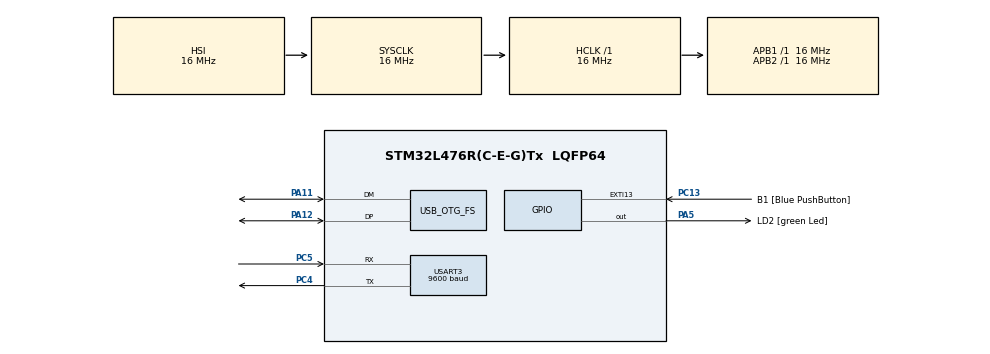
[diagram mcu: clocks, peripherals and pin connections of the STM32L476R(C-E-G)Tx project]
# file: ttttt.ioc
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Mcu.Family=STM32L4
Mcu.Name=STM32L476R(C-E-G)Tx
Mcu.Package=LQFP64
NVIC.OTG_FS_IRQn=true\:0\:0\:false\:false\:true
NVIC.PriorityGroup=NVIC_PRIORITYGROUP_4
PA11.Mode=Host_Only
PA11.Signal=USB_OTG_FS_DM
PA12.Mode=Host_Only
PA12.Signal=USB_OTG_FS_DP
PA13.GPIO_Label=TMS
PA13.Signal=SYS_JTMS-SWDIO
PA14.GPIO_Label=TCK
PA14.Signal=SYS_JTCK-SWCLK
PA2.GPIO_Label=USART_TX
PA2.GPIO_Mode=GPIO_MODE_AF_PP
PA2.GPIO_PuPd=GPIO_NOPULL
PA2.GPIO_Speed=GPIO_SPEED_FREQ_VERY_HIGH
PA2.Signal=USART2_TX
PA3.GPIO_Label=USART_RX
PA3.GPIO_Mode=GPIO_MODE_AF_PP
PA3.GPIO_PuPd=GPIO_NOPULL
PA3.GPIO_Speed=GPIO_SPEED_FREQ_VERY_HIGH
PA3.Signal=USART2_RX
PA5.GPIO_Label=LD2 [green Led]
PA5.GPIO_ModeDefaultOutputPP=GPIO_MODE_OUTPUT_PP
PA5.GPIO_PuPd=GPIO_NOPULL
PA5.GPIO_Speed=GPIO_SPEED_FREQ_LOW
PA5.Signal=GPIO_Output
PB3.GPIO_Label=SWO
PB3.Signal=SYS_JTDO-SWO
PC13.GPIO_Label=B1 [Blue PushButton]
PC13.GPIO_ModeDefaultEXTI=GPIO_MODE_EVT_RISING
PC13.GPIO_PuPd=GPIO_NOPULL
PC13.Signal=GPXTI13
PC14/OSC32_IN.Signal=RCC_OSC32_IN
PC15/OSC32_OUT.Signal=RCC_OSC32_OUT
PC4.Mode=Asynchronous
PC4.Signal=USART3_TX
PC5.Mode=Asynchronous
PC5.Signal=USART3_RX
PH0/OSC_IN.Signal=RCC_OSC_IN
PH1/OSC_OUT.Signal=RCC_OSC_OUT
ProjectManager.HeapSize=0x200
ProjectManager.StackSize=0x400
ProjectManager.TargetToolchain=SW4STM32
RCC.ADCFreq_Value=48000000
RCC.AHBFreq_Value=16000000
RCC.APB1Freq_Value=16000000
RCC.APB1TimFreq_Value=16000000
RCC.APB2Freq_Value=16000000
RCC.APB2TimFreq_Value=16000000
RCC.CK48CLockSelection=RCC_USBCLKSOURCE_PLL
RCC.CortexFreq_Value=16000000
RCC.HCLKFreq_Value=16000000
RCC.HSE_VALUE=8000000
RCC.HSI_VALUE=16000000
RCC.LSE_VALUE=32768
RCC.MSI_VALUE=4000000
RCC.PLLN=24
RCC.PLLSAI1N=24
RCC.PREFETCH_ENABLE=1
RCC.SYSCLKFreq_VALUE=16000000
RCC.SYSCLKSource=RCC_SYSCLKSOURCE_HSI
RCC.USBFreq_Value=48000000
RCC.VCOOutputFreq_Value=96000000
USART3.BaudRate=9600
USART3.WordLength=UART_WORDLENGTH_8B
USB_HOST.USBH_HandleTypeDef=hUsbHostFS
USB_HOST.VirtualModeFS=Hid
USB_OTG_FS.phy_itface=HCD_PHY_EMBEDDED
VP_USB_HOST_VS_USB_HOST_HID_FS.Mode=HID_FS
board=NUCLEO-L476RG

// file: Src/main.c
/**
  ******************************************************************************
  * File Name          : main.c
  * Description        : Main program body
  ******************************************************************************
  *
  * Copyright (c) 2017 STMicroelectronics International N.V.
  * All rights reserved.
  *
  * Redistribution and use in source and binary forms, with or without
  * modification, are permitted, provided that the following conditions are met:
  *
  * 1. Redistribution of source code must retain the above copyright notice,
  *    this list of conditions and the following disclaimer.
  * 2. Redistributions in binary form must reproduce the above copyright notice,
  *    this list of conditions and the following disclaimer in the documentation
  *    and/or other materials provided with the distribution.
  * 3. Neither the name of STMicroelectronics nor the names of other
  *    contributors to this software may be used to endorse or promote products
  *    derived from this software without specific written permission.
  * 4. This software, including modifications and/or derivative works of this
  *    software, must execute solely and exclusively on microcontroller or
  *    microprocessor devices manufactured by or for STMicroelectronics.
  * 5. Redistribution and use of this software other than as permitted under
  *    this license is void and will automatically terminate your rights under
  *    this license.
  *
  * THIS SOFTWARE IS PROVIDED BY STMICROELECTRONICS AND CONTRIBUTORS "AS IS"
  * AND ANY EXPRESS, IMPLIED OR STATUTORY WARRANTIES, INCLUDING, BUT NOT
  * LIMITED TO, THE IMPLIED WARRANTIES OF MERCHANTABILITY, FITNESS FOR A
  * PARTICULAR PURPOSE AND NON-INFRINGEMENT OF THIRD PARTY INTELLECTUAL PROPERTY
  * RIGHTS ARE DISCLAIMED TO THE FULLEST EXTENT PERMITTED BY LAW. IN NO EVENT
  * SHALL STMICROELECTRONICS OR CONTRIBUTORS BE LIABLE FOR ANY DIRECT, INDIRECT,
  * INCIDENTAL, SPECIAL, EXEMPLARY, OR CONSEQUENTIAL DAMAGES (INCLUDING, BUT NOT
  * LIMITED TO, PROCUREMENT OF SUBSTITUTE GOODS OR SERVICES; LOSS OF USE, DATA,
  * OR PROFITS; OR BUSINESS INTERRUPTION) HOWEVER CAUSED AND ON ANY THEORY OF
  * LIABILITY, WHETHER IN CONTRACT, STRICT LIABILITY, OR TORT (INCLUDING
  * NEGLIGENCE OR OTHERWISE) ARISING IN ANY WAY OUT OF THE USE OF THIS SOFTWARE,
  * EVEN IF ADVISED OF THE POSSIBILITY OF SUCH DAMAGE.
  *
  ******************************************************************************
  */
#include "main.h"
#include "stm32l4xx_hal.h"
#include "usb_host.h"
#include "global_var.h"
#include <stdio.h>
#include <stdlib.h>

/* USER CODE BEGIN PV */
/* Private variables ---------------------------------------------------------*/
status = 0;
/* USER CODE END PV */

void SystemClock_Config(void);
void Error_Handler(void);
static void MX_GPIO_Init(void);
static void MX_USART3_UART_Init(void);
void MX_USB_HOST_Process(void);

/* USER CODE BEGIN PFP */
/* Private function prototypes -----------------------------------------------*/

/* USER CODE END PFP */

int main(void)
{

  /* MCU Configuration----------------------------------------------------------*/

  /* Reset of all peripherals, Initializes the Flash interface and the Systick. */
  HAL_Init();

  /* Configure the system clock */
  SystemClock_Config();

  /* Initialize all configured peripherals */
  MX_GPIO_Init();
  MX_USART3_UART_Init();
  MX_USB_HOST_Init();

  /* USER CODE BEGIN 2 */
  Timer_Init();
  PWM_Init();
  /* USER CODE END 2 */

  /* Infinite loop */
  while (1)
  {
    MX_USB_HOST_Process();
  }

}

/** System Clock Configuration
*/
void SystemClock_Config(void)
{

  RCC_OscInitTypeDef RCC_OscInitStruct;
  RCC_ClkInitTypeDef RCC_ClkInitStruct;
  RCC_PeriphCLKInitTypeDef PeriphClkInit;

    /**Initializes the CPU, AHB and APB busses clocks
    */
  RCC_OscInitStruct.OscillatorType = RCC_OSCILLATORTYPE_HSI|RCC_OSCILLATORTYPE_MSI;
  RCC_OscInitStruct.HSIState = RCC_HSI_ON;
  RCC_OscInitStruct.HSICalibrationValue = 16;
  RCC_OscInitStruct.MSIState = RCC_MSI_ON;
  RCC_OscInitStruct.MSICalibrationValue = 0;
  RCC_OscInitStruct.MSIClockRange = RCC_MSIRANGE_6;
  RCC_OscInitStruct.PLL.PLLState = RCC_PLL_ON;
  RCC_OscInitStruct.PLL.PLLSource = RCC_PLLSOURCE_MSI;
  RCC_OscInitStruct.PLL.PLLM = 1;
  RCC_OscInitStruct.PLL.PLLN = 24;
  RCC_OscInitStruct.PLL.PLLP = RCC_PLLP_DIV7;
  RCC_OscInitStruct.PLL.PLLQ = RCC_PLLQ_DIV2;
  RCC_OscInitStruct.PLL.PLLR = RCC_PLLR_DIV2;
  if (HAL_RCC_OscConfig(&RCC_OscInitStruct) != HAL_OK)
  {
    Error_Handler();
  }

    /**Initializes the CPU, AHB and APB busses clocks
    */
  RCC_ClkInitStruct.ClockType = RCC_CLOCKTYPE_HCLK|RCC_CLOCKTYPE_SYSCLK
                              |RCC_CLOCKTYPE_PCLK1|RCC_CLOCKTYPE_PCLK2;
  RCC_ClkInitStruct.SYSCLKSource = RCC_SYSCLKSOURCE_HSI;
  RCC_ClkInitStruct.AHBCLKDivider = RCC_SYSCLK_DIV1;
  RCC_ClkInitStruct.APB1CLKDivider = RCC_HCLK_DIV1;
  RCC_ClkInitStruct.APB2CLKDivider = RCC_HCLK_DIV1;

  if (HAL_RCC_ClockConfig(&RCC_ClkInitStruct, FLASH_LATENCY_0) != HAL_OK)
  {
    Error_Handler();
  }

  PeriphClkInit.PeriphClockSelection = RCC_PERIPHCLK_USART3|RCC_PERIPHCLK_USB;
  PeriphClkInit.Usart3ClockSelection = RCC_USART3CLKSOURCE_PCLK1;
  PeriphClkInit.UsbClockSelection = RCC_USBCLKSOURCE_PLL;
  if (HAL_RCCEx_PeriphCLKConfig(&PeriphClkInit) != HAL_OK)
  {
    Error_Handler();
  }

    /**Configure the main internal regulator output voltage
    */
  if (HAL_PWREx_ControlVoltageScaling(PWR_REGULATOR_VOLTAGE_SCALE1) != HAL_OK)
  {
    Error_Handler();
  }

    /**Configure the Systick interrupt time
    */
  HAL_SYSTICK_Config(HAL_RCC_GetHCLKFreq()/1000);

    /**Configure the Systick
    */
  HAL_SYSTICK_CLKSourceConfig(SYSTICK_CLKSOURCE_HCLK);

    /**Enable MSI Auto calibration
    */
  HAL_RCCEx_EnableMSIPLLMode();

  /* SysTick_IRQn interrupt configuration */
  HAL_NVIC_SetPriority(SysTick_IRQn, 0, 0);
}

/* USART3 init function */
static void MX_USART3_UART_Init(void)
{

  huart3.Instance = USART3;
  huart3.Init.BaudRate = 9600;
  huart3.Init.WordLength = UART_WORDLENGTH_8B;
  huart3.Init.StopBits = UART_STOPBITS_1;
  huart3.Init.Parity = UART_PARITY_NONE;
  huart3.Init.Mode = UART_MODE_TX_RX;
  huart3.Init.HwFlowCtl = UART_HWCONTROL_NONE;
  huart3.Init.OverSampling = UART_OVERSAMPLING_16;
  huart3.Init.OneBitSampling = UART_ONE_BIT_SAMPLE_DISABLE;
  huart3.AdvancedInit.AdvFeatureInit = UART_ADVFEATURE_NO_INIT;
  if (HAL_UART_Init(&huart3) != HAL_OK)
  {
    Error_Handler();
  }

}

/** Configure pins as
        * Analog
        * Input
        * Output
        * EVENT_OUT
        * EXTI
     PA2   ------> USART2_TX
     PA3   ------> USART2_RX
*/
static void MX_GPIO_Init(void)
{

  GPIO_InitTypeDef GPIO_InitStruct;

  /* GPIO Ports Clock Enable */
  __HAL_RCC_GPIOC_CLK_ENABLE();
  __HAL_RCC_GPIOH_CLK_ENABLE();
  __HAL_RCC_GPIOA_CLK_ENABLE();
  __HAL_RCC_GPIOB_CLK_ENABLE();

  /*Configure GPIO pin : B1_Pin */
  GPIO_InitStruct.Pin = B1_Pin;
  GPIO_InitStruct.Mode = GPIO_MODE_EVT_RISING;
  GPIO_InitStruct.Pull = GPIO_NOPULL;
  HAL_GPIO_Init(B1_GPIO_Port, &GPIO_InitStruct);

  /*Configure GPIO pins : USART_TX_Pin USART_RX_Pin */
  GPIO_InitStruct.Pin = USART_TX_Pin|USART_RX_Pin;
  GPIO_InitStruct.Mode = GPIO_MODE_AF_PP;
  GPIO_InitStruct.Pull = GPIO_NOPULL;
  GPIO_InitStruct.Speed = GPIO_SPEED_FREQ_VERY_HIGH;
  GPIO_InitStruct.Alternate = GPIO_AF7_USART2;
  HAL_GPIO_Init(GPIOA, &GPIO_InitStruct);

  /*Configure GPIO pin : LD2_Pin */
  GPIO_InitStruct.Pin = LD2_Pin;
  GPIO_InitStruct.Mode = GPIO_MODE_OUTPUT_PP;
  GPIO_InitStruct.Pull = GPIO_NOPULL;
  GPIO_InitStruct.Speed = GPIO_SPEED_FREQ_LOW;
  HAL_GPIO_Init(LD2_GPIO_Port, &GPIO_InitStruct);

  /*Configure GPIO pin Output Level */
  HAL_GPIO_WritePin(LD2_GPIO_Port, LD2_Pin, GPIO_PIN_RESET);

  /* PB6,8,9 TIM4->CH1,3,4 */
  GPIO_InitStruct.Pin = GPIO_PIN_6 | GPIO_PIN_8 | GPIO_PIN_9;
	GPIO_InitStruct.Mode = GPIO_MODE_AF_PP;
	GPIO_InitStruct.Pull = GPIO_NOPULL;
	GPIO_InitStruct.Speed = GPIO_SPEED_FREQ_VERY_HIGH;
	GPIO_InitStruct.Alternate = GPIO_AF2_TIM2;
	HAL_GPIO_Init(GPIOB, &GPIO_InitStruct);

}

/* USER CODE BEGIN 4 */
void TIM3_IRQHandler() {
	if (status == 2) {
		Decrease();
	}
	TIM3->SR &= ~TIM_SR_UIF;
}

void Increase() {
	if (stamina_red < 256) {
		stamina_red += 8;
	} else {
		stamina_red = 256;
	}
	if (stamina_green > 0) {
		stamina_green -= 8;
	}
	if (stamina_green < 0) {
		stamina_green = 0;
	}
	Set_Color(stamina_red, stamina_green, 0);
}

void Decrease() {
	if (stamina_green < 256) {
		stamina_green += 4;
	} else {
		stamina_green = 256;
	}
	if (stamina_red > 0) {
		stamina_red -= 4;
	}
	if (stamina_red < 0) {
		stamina_red = 0;
	}
	Set_Color(stamina_red, stamina_green, 0);
}

void Breath() {
	uint32_t red = rand() % 256;
	uint32_t green = rand() % 256;
	uint32_t blue = rand() % 256;
	uint32_t red_cnt = 0;
	uint32_t blue_cnt = 0;
	uint32_t green_cnt = 0;
	int count = 0;
	while (count < 500) {
		count++;
		red_cnt += red / 5;
		green_cnt += green / 5;
		blue_cnt += blue / 5;
		TIM4->CCR1 = (uint32_t)(red_cnt);
		TIM4->CCR3 = (uint32_t)(green_cnt);
		TIM4->CCR4 = (uint32_t)(blue_cnt);
		HAL_Delay(2);
	}
	while (count > 0) {
		count--;
		red_cnt -= red / 5;
		green_cnt -= green / 5;
		blue_cnt -= blue / 5;
		if (red_cnt < 0) {
			red_cnt = 0;
		}
		if (green_cnt < 0) {
			green_cnt = 0;
		}
		if (blue_cnt < 0) {
			blue_cnt = 0;
		}
		TIM4->CCR1 = (uint32_t)(red_cnt);
		TIM4->CCR3 = (uint32_t)(green_cnt);
		TIM4->CCR4 = (uint32_t)(blue_cnt);
		HAL_Delay(2);
	}
	Set_Color(0, 0, 0);
}

void Set_Color(uint32_t red, uint32_t green, uint32_t blue) {
	TIM4->CCR1 = (uint32_t)(red * 100);
	TIM4->CCR3 = (uint32_t)(green * 100);
	TIM4->CCR4 = (uint32_t)(blue * 100);
}

void Timer_Init() {
	RCC->APB1ENR1 |= RCC_APB1ENR1_TIM4EN | RCC_APB1ENR1_TIM3EN;
	TIM4->PSC = (uint32_t)(1 - 1);
	TIM4->ARR = (uint32_t)(25601);
	TIM4->EGR = TIM_EGR_UG;
	TIM4->CR1 |= TIM_CR1_CEN;

	TIM3->PSC = (uint32_t)(1600 - 1);
	TIM3->ARR = (uint32_t)(500 - 1);
	TIM3->EGR = TIM_EGR_UG;
	TIM3->DIER = TIM_DIER_UIE;
	TIM3->CR1 |= TIM_CR1_CEN;

	NVIC_EnableIRQ(TIM3_IRQn);
	NVIC_SetPriority(TIM3_IRQn, 10);
}

void PWM_Init() {
	TIM4->CCMR1 |= TIM_CCMR1_OC1PE | TIM_CCMR1_OC1M;
	TIM4->CCMR2 |= TIM_CCMR2_OC3PE | TIM_CCMR2_OC3M | TIM_CCMR2_OC4PE | TIM_CCMR2_OC4M;
	TIM4->CCER |= TIM_CCER_CC1E | TIM_CCER_CC3E | TIM_CCER_CC4E;
	TIM4->CCR1 = (uint32_t)(1 - 1);
	TIM4->CCR3 = (uint32_t)(1 - 1);
	TIM4->CCR4 = (uint32_t)(1 - 1);
}

/* USER CODE END 4 */

void Error_Handler(void)
{
  while(1)
  {
  }
}

/************************ (C) COPYRIGHT STMicroelectronics *****END OF FILE****/
